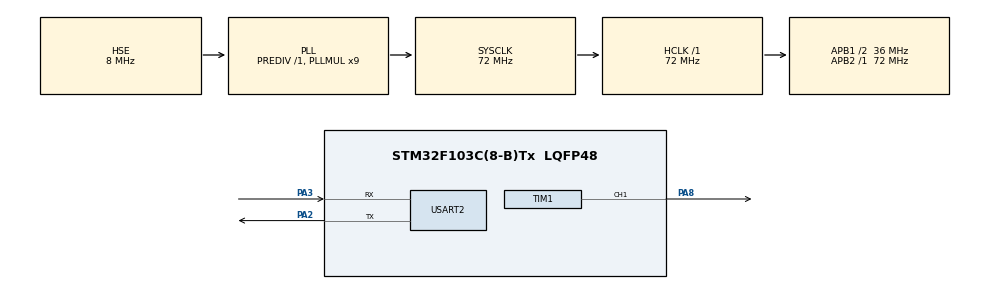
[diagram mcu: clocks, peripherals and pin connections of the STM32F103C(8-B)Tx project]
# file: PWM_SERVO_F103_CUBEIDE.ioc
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Mcu.Family=STM32F1
Mcu.Name=STM32F103C(8-B)Tx
Mcu.Package=LQFP48
NVIC.PriorityGroup=NVIC_PRIORITYGROUP_4
NVIC.USART2_IRQn=true\:0\:0\:false\:false\:true\:true\:true
PA13.Mode=Serial_Wire
PA13.Signal=SYS_JTMS-SWDIO
PA14.Mode=Serial_Wire
PA14.Signal=SYS_JTCK-SWCLK
PA2.Mode=Asynchronous
PA2.Signal=USART2_TX
PA3.Mode=Asynchronous
PA3.Signal=USART2_RX
PA8.Signal=S_TIM1_CH1
PD0-OSC_IN.Mode=HSE-External-Oscillator
PD0-OSC_IN.Signal=RCC_OSC_IN
PD1-OSC_OUT.Mode=HSE-External-Oscillator
PD1-OSC_OUT.Signal=RCC_OSC_OUT
ProjectManager.HeapSize=0x200
ProjectManager.StackSize=0x400
ProjectManager.TargetToolchain=STM32CubeIDE
RCC.AHBFreq_Value=72000000
RCC.APB1CLKDivider=RCC_HCLK_DIV2
RCC.APB1Freq_Value=36000000
RCC.APB1TimFreq_Value=72000000
RCC.APB2Freq_Value=72000000
RCC.APB2TimFreq_Value=72000000
RCC.HCLKFreq_Value=72000000
RCC.PLLMUL=RCC_PLL_MUL9
RCC.PLLSourceVirtual=RCC_PLLSOURCE_HSE
RCC.SYSCLKFreq_VALUE=72000000
RCC.SYSCLKSource=RCC_SYSCLKSOURCE_PLLCLK
RCC.USBFreq_Value=72000000
SH.S_TIM1_CH1.0=TIM1_CH1,PWM Generation1 CH1
TIM1.Channel-PWM\ Generation1\ CH1=TIM_CHANNEL_1
TIM1.Period=100-1
TIM1.Prescaler=7200-1
USART2.VirtualMode=VM_ASYNC
VP_TIM1_VS_ClockSourceINT.Mode=Internal
board=custom

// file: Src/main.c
/* USER CODE BEGIN Header */
/**
  ******************************************************************************
  * @file           : main.c
  * @brief          : Main program body

  ******************************************************************************
  * @attention
  *
  * <h2><center>&copy; Copyright (c) 2019 STMicroelectronics.
  * All rights reserved.</center></h2>
  *
  * This software component is licensed by ST under BSD 3-Clause license,
  * the "License"; You may not use this file except in compliance with the
  * License. You may obtain a copy of the License at:
  *                        opensource.org/licenses/BSD-3-Clause
  *
  ********************************Writed By SaygınSİSMAN**********************************************
  */
/* USER CODE END Header */

#include "main.h"

TIM_HandleTypeDef htim1;

UART_HandleTypeDef huart2;

void SystemClock_Config(void);
static void MX_GPIO_Init(void);
static void MX_TIM1_Init(void);
static void MX_USART2_UART_Init(void);

/* USER CODE BEGIN 0 */

uint8_t rx_data;

void HAL_UART_RxCpltCallback(UART_HandleTypeDef *huart)
{
	//HAL_UART_Transmit(&huart2,&rx_data, 1, 100);

	if (rx_data == '1')
	{

		htim1.Instance->CCR1 = 5; // 0.5ms pulse

	}
	else if (rx_data == '2')
	{

		htim1.Instance->CCR1 = 15; // 1 ms pulse

	}
	else if (rx_data == '3')
	{

		htim1.Instance->CCR1 = 25; // 2.5ms pulse

	}

	HAL_UART_Receive_IT(&huart2, &rx_data, 1);
}
/* USER CODE END 0 */

int main(void)
{

  /* MCU Configuration--------------------------------------------------------*/

  /* Reset of all peripherals, Initializes the Flash interface and the Systick. */
  HAL_Init();

  /* Configure the system clock */
  SystemClock_Config();

  /* Initialize all configured peripherals */
  MX_GPIO_Init();
  MX_TIM1_Init();
  MX_USART2_UART_Init();
  /* USER CODE BEGIN 2 */

  HAL_TIM_PWM_Start(&htim1, TIM_CHANNEL_1);
  HAL_UART_Receive_IT(&huart2, &rx_data, 1);

  /* USER CODE END 2 */

  /* Infinite loop */
  while (1)
  {

  }
}

void SystemClock_Config(void)
{
  RCC_OscInitTypeDef RCC_OscInitStruct = {0};
  RCC_ClkInitTypeDef RCC_ClkInitStruct = {0};

  /** Initializes the CPU, AHB and APB busses clocks
  */
  RCC_OscInitStruct.OscillatorType = RCC_OSCILLATORTYPE_HSE;
  RCC_OscInitStruct.HSEState = RCC_HSE_ON;
  RCC_OscInitStruct.HSEPredivValue = RCC_HSE_PREDIV_DIV1;
  RCC_OscInitStruct.HSIState = RCC_HSI_ON;
  RCC_OscInitStruct.PLL.PLLState = RCC_PLL_ON;
  RCC_OscInitStruct.PLL.PLLSource = RCC_PLLSOURCE_HSE;
  RCC_OscInitStruct.PLL.PLLMUL = RCC_PLL_MUL9;
  if (HAL_RCC_OscConfig(&RCC_OscInitStruct) != HAL_OK)
  {
    Error_Handler();
  }
  /** Initializes the CPU, AHB and APB busses clocks
  */
  RCC_ClkInitStruct.ClockType = RCC_CLOCKTYPE_HCLK|RCC_CLOCKTYPE_SYSCLK
                              |RCC_CLOCKTYPE_PCLK1|RCC_CLOCKTYPE_PCLK2;
  RCC_ClkInitStruct.SYSCLKSource = RCC_SYSCLKSOURCE_PLLCLK;
  RCC_ClkInitStruct.AHBCLKDivider = RCC_SYSCLK_DIV1;
  RCC_ClkInitStruct.APB1CLKDivider = RCC_HCLK_DIV2;
  RCC_ClkInitStruct.APB2CLKDivider = RCC_HCLK_DIV1;

  if (HAL_RCC_ClockConfig(&RCC_ClkInitStruct, FLASH_LATENCY_2) != HAL_OK)
  {
    Error_Handler();
  }
}

static void MX_TIM1_Init(void)
{

  TIM_ClockConfigTypeDef sClockSourceConfig = {0};
  TIM_MasterConfigTypeDef sMasterConfig = {0};
  TIM_OC_InitTypeDef sConfigOC = {0};
  TIM_BreakDeadTimeConfigTypeDef sBreakDeadTimeConfig = {0};

  htim1.Instance = TIM1;
  htim1.Init.Prescaler = 7200-1;
  htim1.Init.CounterMode = TIM_COUNTERMODE_UP;
  htim1.Init.Period = 100-1;
  htim1.Init.ClockDivision = TIM_CLOCKDIVISION_DIV1;
  htim1.Init.RepetitionCounter = 0;
  htim1.Init.AutoReloadPreload = TIM_AUTORELOAD_PRELOAD_DISABLE;
  if (HAL_TIM_Base_Init(&htim1) != HAL_OK)
  {
    Error_Handler();
  }
  sClockSourceConfig.ClockSource = TIM_CLOCKSOURCE_INTERNAL;
  if (HAL_TIM_ConfigClockSource(&htim1, &sClockSourceConfig) != HAL_OK)
  {
    Error_Handler();
  }
  if (HAL_TIM_PWM_Init(&htim1) != HAL_OK)
  {
    Error_Handler();
  }
  sMasterConfig.MasterOutputTrigger = TIM_TRGO_RESET;
  sMasterConfig.MasterSlaveMode = TIM_MASTERSLAVEMODE_DISABLE;
  if (HAL_TIMEx_MasterConfigSynchronization(&htim1, &sMasterConfig) != HAL_OK)
  {
    Error_Handler();
  }
  sConfigOC.OCMode = TIM_OCMODE_PWM1;
  sConfigOC.Pulse = 0;
  sConfigOC.OCPolarity = TIM_OCPOLARITY_HIGH;
  sConfigOC.OCNPolarity = TIM_OCNPOLARITY_HIGH;
  sConfigOC.OCFastMode = TIM_OCFAST_DISABLE;
  sConfigOC.OCIdleState = TIM_OCIDLESTATE_RESET;
  sConfigOC.OCNIdleState = TIM_OCNIDLESTATE_RESET;
  if (HAL_TIM_PWM_ConfigChannel(&htim1, &sConfigOC, TIM_CHANNEL_1) != HAL_OK)
  {
    Error_Handler();
  }
  sBreakDeadTimeConfig.OffStateRunMode = TIM_OSSR_DISABLE;
  sBreakDeadTimeConfig.OffStateIDLEMode = TIM_OSSI_DISABLE;
  sBreakDeadTimeConfig.LockLevel = TIM_LOCKLEVEL_OFF;
  sBreakDeadTimeConfig.DeadTime = 0;
  sBreakDeadTimeConfig.BreakState = TIM_BREAK_DISABLE;
  sBreakDeadTimeConfig.BreakPolarity = TIM_BREAKPOLARITY_HIGH;
  sBreakDeadTimeConfig.AutomaticOutput = TIM_AUTOMATICOUTPUT_DISABLE;
  if (HAL_TIMEx_ConfigBreakDeadTime(&htim1, &sBreakDeadTimeConfig) != HAL_OK)
  {
    Error_Handler();
  }
  HAL_TIM_MspPostInit(&htim1);

}

static void MX_USART2_UART_Init(void)
{

  huart2.Instance = USART2;
  huart2.Init.BaudRate = 115200;
  huart2.Init.WordLength = UART_WORDLENGTH_8B;
  huart2.Init.StopBits = UART_STOPBITS_1;
  huart2.Init.Parity = UART_PARITY_NONE;
  huart2.Init.Mode = UART_MODE_TX_RX;
  huart2.Init.HwFlowCtl = UART_HWCONTROL_NONE;
  huart2.Init.OverSampling = UART_OVERSAMPLING_16;
  if (HAL_UART_Init(&huart2) != HAL_OK)
  {
    Error_Handler();
  }

}

static void MX_GPIO_Init(void)
{
  GPIO_InitTypeDef GPIO_InitStruct = {0};

  /* GPIO Ports Clock Enable */
  __HAL_RCC_GPIOD_CLK_ENABLE();
  __HAL_RCC_GPIOA_CLK_ENABLE();
  __HAL_RCC_GPIOB_CLK_ENABLE();

  /*Configure GPIO pin Output Level */
  HAL_GPIO_WritePin(GPIOA, GPIO_PIN_6|GPIO_PIN_7, GPIO_PIN_RESET);

  /*Configure GPIO pin Output Level */
  HAL_GPIO_WritePin(GPIOB, GPIO_PIN_0, GPIO_PIN_RESET);

  /*Configure GPIO pins : PA6 PA7 */
  GPIO_InitStruct.Pin = GPIO_PIN_6|GPIO_PIN_7;
  GPIO_InitStruct.Mode = GPIO_MODE_OUTPUT_PP;
  GPIO_InitStruct.Pull = GPIO_NOPULL;
  GPIO_InitStruct.Speed = GPIO_SPEED_FREQ_LOW;
  HAL_GPIO_Init(GPIOA, &GPIO_InitStruct);

  /*Configure GPIO pin : PB0 */
  GPIO_InitStruct.Pin = GPIO_PIN_0;
  GPIO_InitStruct.Mode = GPIO_MODE_OUTPUT_PP;
  GPIO_InitStruct.Pull = GPIO_NOPULL;
  GPIO_InitStruct.Speed = GPIO_SPEED_FREQ_LOW;
  HAL_GPIO_Init(GPIOB, &GPIO_InitStruct);

}

void Error_Handler(void)
{
}

/************************ (C) COPYRIGHT STMicroelectronics *****END OF FILE****/
